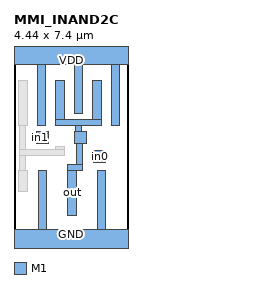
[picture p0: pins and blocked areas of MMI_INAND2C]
MACRO MMI_INAND2C
	CLASS CORE ;
	FOREIGN MMI_INAND2C 0 0 ;
	SIZE 4.44 BY 7.4 ;
	SYMMETRY X Y ;
	SITE CORE1 ;
	PIN out
		DIRECTION output ;
		USE SIGNAL ;
		PORT
			LAYER M1 ;
			RECT 1.62 4.765 1.96 6.295 ;
			LAYER M1 ;
			RECT 3.06 4.765 3.4 6.295 ;
			LAYER M1 ;
			RECT 1.62 4.535 3.4 4.765 ;
			LAYER M1 ;
			RECT 2.405 4.295 2.635 4.535 ;
			LAYER M1 ;
			RECT 2.365 3.845 2.815 4.295 ;
			LAYER M1 ;
			RECT 2.425 3.02 2.655 3.845 ;
			LAYER M1 ;
			RECT 2.09 2.79 2.655 3.02 ;
			LAYER M1 ;
			RECT 2.09 1.03 2.43 2.79 ;
		END
		AntennaDiffArea 2.9808 ;
	END out
	PIN in1
		DIRECTION input ;
		USE SIGNAL ;
		PORT
			LAYER M1 ;
			RECT 0.885 4.24 1.335 4.295 ;
			LAYER M1 ;
			RECT 0.705 3.9 1.335 4.24 ;
			LAYER M1 ;
			RECT 0.885 3.845 1.335 3.9 ;
		END
		AntennaGateArea 0.4968 ;
	END in1
	PIN GND
		DIRECTION inout ;
		USE GROUND ;
		PORT
			LAYER M1 ;
			RECT 0.94 0.5 1.28 2.79 ;
			LAYER M1 ;
			RECT 3.24 0.5 3.58 2.79 ;
			LAYER M1 ;
			RECT 0 -0.5 4.44 0.5 ;
		END
	END GND
	PIN VDD
		DIRECTION inout ;
		USE POWER ;
		PORT
			LAYER M1 ;
			RECT 0 6.9 4.44 7.9 ;
			LAYER M1 ;
			RECT 0.9 4.535 1.24 6.9 ;
			LAYER M1 ;
			RECT 2.34 5.015 2.68 6.9 ;
			LAYER M1 ;
			RECT 3.78 4.535 4.12 6.9 ;
		END
	END VDD
	PIN in0
		DIRECTION input ;
		USE SIGNAL ;
		PORT
			LAYER M1 ;
			RECT 3.105 3.105 3.555 3.555 ;
		END
		AntennaGateArea 1.3248 ;
	END in0
	OBS
		LAYER M1 ;
		RECT 0.18 4.535 0.52 6.295 ;
		LAYER M1 ;
		RECT 0.225 3.6 0.455 4.535 ;
		LAYER M1 ;
		RECT 1.61 3.6 1.95 3.71 ;
		LAYER M1 ;
		RECT 0.225 3.37 1.95 3.6 ;
		LAYER M1 ;
		RECT 0.225 2.79 0.455 3.37 ;
		LAYER M1 ;
		RECT 0.18 1.95 0.52 2.79 ;
	END
END MMI_INAND2C
